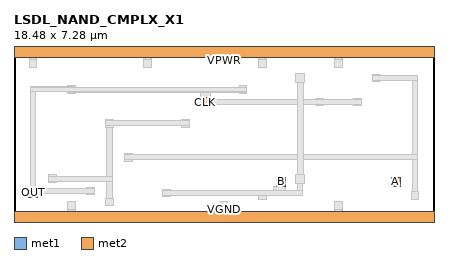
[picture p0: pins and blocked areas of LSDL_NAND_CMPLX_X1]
MACRO LSDL_NAND_CMPLX_X1
 CLASS CORE ;
 FOREIGN LSDL_NAND_CMPLX_X1 0 0 ;
 SIZE 18.48 BY 7.28 ;
 ORIGIN 0 0 ;
 SYMMETRY X Y R90 ;
 SITE unit ;
  PIN VPWR
   DIRECTION INOUT ;
   USE POWER ;
   SHAPE ABUTMENT ;
    PORT
     CLASS CORE ;
       LAYER met1 ;
        RECT 0.00000000 7.04000000 18.48000000 7.52000000 ;
       LAYER met2 ;
        RECT 0.00000000 7.04000000 18.48000000 7.52000000 ;
    END
  END VPWR

  PIN VGND
   DIRECTION INOUT ;
   USE POWER ;
   SHAPE ABUTMENT ;
    PORT
     CLASS CORE ;
       LAYER met1 ;
        RECT 0.00000000 -0.24000000 18.48000000 0.24000000 ;
       LAYER met2 ;
        RECT 0.00000000 -0.24000000 18.48000000 0.24000000 ;
    END
  END VGND

  PIN OUT
   DIRECTION INOUT ;
   USE SIGNAL ;
   SHAPE ABUTMENT ;
    PORT
     CLASS CORE ;
       LAYER met2 ;
        RECT 0.64000000 0.86000000 1.04000000 1.26000000 ;
    END
  END OUT

  PIN CLK
   DIRECTION INOUT ;
   USE SIGNAL ;
   SHAPE ABUTMENT ;
    PORT
     CLASS CORE ;
       LAYER met2 ;
        RECT 8.20000000 4.85700000 8.60000000 5.25700000 ;
    END
  END CLK

  PIN B
   DIRECTION INOUT ;
   USE SIGNAL ;
   SHAPE ABUTMENT ;
    PORT
     CLASS CORE ;
       LAYER met2 ;
        RECT 11.56000000 1.34700000 11.96000000 1.74700000 ;
    END
  END B

  PIN A
   DIRECTION INOUT ;
   USE SIGNAL ;
   SHAPE ABUTMENT ;
    PORT
     CLASS CORE ;
       LAYER met2 ;
        RECT 16.60000000 1.34700000 17.00000000 1.74700000 ;
    END
  END A

 OBS
    LAYER polycont ;
     RECT 11.65000000 1.43700000 11.87000000 1.65700000 ;
     RECT 8.29000000 4.94700000 8.51000000 5.16700000 ;
     RECT 13.33000000 4.94700000 13.55000000 5.16700000 ;
     RECT 15.01000000 4.94700000 15.23000000 5.16700000 ;
     RECT 3.25000000 1.03200000 3.47000000 1.25200000 ;
     RECT 9.97000000 5.48700000 10.19000000 5.70700000 ;
     RECT 4.93000000 2.51700000 5.15000000 2.73700000 ;
     RECT 6.61000000 0.95000000 6.83000000 1.17000000 ;
     RECT 16.69000000 1.43700000 16.91000000 1.65700000 ;
     RECT 1.57000000 1.57200000 1.79000000 1.79200000 ;

    LAYER pdiffc ;
     RECT 2.41000000 5.51000000 2.63000000 5.73000000 ;
     RECT 0.73000000 6.65000000 0.95000000 6.87000000 ;
     RECT 5.77000000 6.65000000 5.99000000 6.87000000 ;
     RECT 10.81000000 6.65000000 11.03000000 6.87000000 ;
     RECT 14.17000000 6.65000000 14.39000000 6.87000000 ;
     RECT 15.85000000 6.01000000 16.07000000 6.23000000 ;
     RECT 12.49000000 6.01000000 12.71000000 6.23000000 ;
     RECT 4.09000000 4.01000000 4.31000000 4.23000000 ;
     RECT 7.45000000 4.01000000 7.67000000 4.23000000 ;

    LAYER ndiffc ;
     RECT 0.73000000 0.95000000 0.95000000 1.17000000 ;
     RECT 17.53000000 0.85000000 17.75000000 1.07000000 ;
     RECT 2.41000000 0.41000000 2.63000000 0.63000000 ;
     RECT 9.13000000 0.41000000 9.35000000 0.63000000 ;
     RECT 14.17000000 0.41000000 14.39000000 0.63000000 ;
     RECT 10.81000000 0.85000000 11.03000000 1.07000000 ;
     RECT 4.09000000 0.55000000 4.31000000 0.77000000 ;

    LAYER met1 ;
     RECT 2.35000000 0.24000000 2.40500000 0.35000000 ;
     RECT 2.63500000 0.24000000 2.69000000 0.35000000 ;
     RECT 9.07000000 0.24000000 9.12500000 0.35000000 ;
     RECT 9.35500000 0.24000000 9.41000000 0.35000000 ;
     RECT 14.11000000 0.24000000 14.16500000 0.35000000 ;
     RECT 14.39500000 0.24000000 14.45000000 0.35000000 ;
     RECT 11.40700000 1.17500000 11.96000000 1.34700000 ;
     RECT 8.60000000 5.17200000 8.86200000 5.25700000 ;
     RECT 8.20000000 5.25700000 8.64800000 5.48200000 ;
     RECT 0.67000000 6.93000000 0.72500000 7.04000000 ;
     RECT 0.95500000 6.93000000 1.01000000 7.04000000 ;
     RECT 5.71000000 6.93000000 5.76500000 7.04000000 ;
     RECT 5.99500000 6.93000000 6.05000000 7.04000000 ;
     RECT 10.75000000 6.93000000 10.80500000 7.04000000 ;
     RECT 11.03500000 6.93000000 11.09000000 7.04000000 ;
     RECT 14.11000000 6.93000000 14.16500000 7.04000000 ;
     RECT 14.39500000 6.93000000 14.45000000 7.04000000 ;
     RECT 11.56000000 1.34700000 11.96000000 1.74700000 ;
     RECT 8.20000000 4.85700000 8.60000000 4.94200000 ;
     RECT 13.27000000 4.88700000 13.61000000 4.94200000 ;
     RECT 14.95000000 4.88700000 15.29000000 4.94200000 ;
     RECT 8.20000000 4.94200000 15.29000000 5.17200000 ;
     RECT 13.27000000 5.17200000 13.61000000 5.22700000 ;
     RECT 14.95000000 5.17200000 15.29000000 5.22700000 ;
     RECT 8.20000000 5.17200000 8.60000000 5.25700000 ;
     RECT 0.64000000 0.86000000 1.04000000 1.02700000 ;
     RECT 3.19000000 0.97200000 3.53000000 1.02700000 ;
     RECT 0.64000000 1.02700000 3.53000000 1.25700000 ;
     RECT 0.64000000 1.25700000 1.04000000 1.26000000 ;
     RECT 3.19000000 1.25700000 3.53000000 1.31200000 ;
     RECT 2.35000000 5.45000000 2.69000000 5.48200000 ;
     RECT 9.91000000 5.42700000 10.25000000 5.48200000 ;
     RECT 0.72500000 1.26000000 0.95500000 5.50500000 ;
     RECT 2.35000000 5.48200000 10.25000000 5.50500000 ;
     RECT 0.72500000 5.50500000 10.25000000 5.71200000 ;
     RECT 0.72500000 5.71200000 2.69000000 5.73500000 ;
     RECT 9.91000000 5.71200000 10.25000000 5.76700000 ;
     RECT 2.35000000 5.73500000 2.69000000 5.79000000 ;
     RECT 0.67000000 6.59000000 1.01000000 6.93000000 ;
     RECT 5.71000000 6.59000000 6.05000000 6.93000000 ;
     RECT 10.75000000 6.59000000 11.09000000 6.93000000 ;
     RECT 14.11000000 6.59000000 14.45000000 6.93000000 ;
     RECT 0.72500000 6.93000000 0.95500000 7.04000000 ;
     RECT 5.76500000 6.93000000 5.99500000 7.04000000 ;
     RECT 10.80500000 6.93000000 11.03500000 7.04000000 ;
     RECT 14.16500000 6.93000000 14.39500000 7.04000000 ;
     RECT 0.00000000 7.04000000 18.48000000 7.52000000 ;
     RECT 17.47000000 0.79000000 17.81000000 1.13000000 ;
     RECT 4.87000000 2.45700000 5.21000000 2.51200000 ;
     RECT 17.52500000 1.13000000 17.75500000 2.51200000 ;
     RECT 4.87000000 2.51200000 17.75500000 2.74200000 ;
     RECT 4.87000000 2.74200000 5.21000000 2.79700000 ;
     RECT 15.79000000 5.95000000 16.13000000 6.00500000 ;
     RECT 17.52500000 2.74200000 17.75500000 6.00500000 ;
     RECT 15.79000000 6.00500000 17.75500000 6.23500000 ;
     RECT 15.79000000 6.23500000 16.13000000 6.29000000 ;
     RECT 0.00000000 -0.24000000 18.48000000 0.24000000 ;
     RECT 2.40500000 0.24000000 2.63500000 0.35000000 ;
     RECT 9.12500000 0.24000000 9.35500000 0.35000000 ;
     RECT 14.16500000 0.24000000 14.39500000 0.35000000 ;
     RECT 2.35000000 0.35000000 2.69000000 0.69000000 ;
     RECT 9.07000000 0.35000000 9.41000000 0.69000000 ;
     RECT 14.11000000 0.35000000 14.45000000 0.69000000 ;
     RECT 6.55000000 0.89000000 6.89000000 0.94500000 ;
     RECT 10.75000000 0.79000000 11.09000000 0.94500000 ;
     RECT 6.55000000 0.94500000 12.71500000 1.17500000 ;
     RECT 6.55000000 1.17500000 6.89000000 1.23000000 ;
     RECT 12.48500000 1.17500000 12.71500000 1.48200000 ;
     RECT 12.40000000 1.48200000 12.80000000 1.88200000 ;
     RECT 12.40000000 5.92000000 12.80000000 6.32000000 ;
     RECT 16.60000000 1.34700000 17.00000000 1.74700000 ;
     RECT 4.03000000 0.49000000 4.37000000 0.83000000 ;
     RECT 1.51000000 1.51200000 1.85000000 1.56700000 ;
     RECT 4.08500000 0.83000000 4.31500000 1.56700000 ;
     RECT 1.51000000 1.56700000 4.31500000 1.79700000 ;
     RECT 1.51000000 1.79700000 1.85000000 1.85200000 ;
     RECT 4.08500000 1.79700000 4.31500000 3.95000000 ;
     RECT 4.03000000 3.95000000 4.37000000 4.00500000 ;
     RECT 7.39000000 3.95000000 7.73000000 4.00500000 ;
     RECT 4.03000000 4.00500000 7.73000000 4.23500000 ;
     RECT 4.03000000 4.23500000 4.37000000 4.29000000 ;
     RECT 7.39000000 4.23500000 7.73000000 4.29000000 ;

    LAYER via1 ;
     RECT 11.63000000 1.41700000 11.89000000 1.67700000 ;
     RECT 8.27000000 4.92700000 8.53000000 5.18700000 ;
     RECT 0.71000000 0.93000000 0.97000000 1.19000000 ;
     RECT 0.71000000 7.15000000 0.97000000 7.41000000 ;
     RECT 2.39000000 7.15000000 2.65000000 7.41000000 ;
     RECT 4.07000000 7.15000000 4.33000000 7.41000000 ;
     RECT 5.75000000 7.15000000 6.01000000 7.41000000 ;
     RECT 7.43000000 7.15000000 7.69000000 7.41000000 ;
     RECT 9.11000000 7.15000000 9.37000000 7.41000000 ;
     RECT 10.79000000 7.15000000 11.05000000 7.41000000 ;
     RECT 12.47000000 7.15000000 12.73000000 7.41000000 ;
     RECT 14.15000000 7.15000000 14.41000000 7.41000000 ;
     RECT 15.83000000 7.15000000 16.09000000 7.41000000 ;
     RECT 17.51000000 7.15000000 17.77000000 7.41000000 ;
     RECT 0.71000000 -0.13000000 0.97000000 0.13000000 ;
     RECT 2.39000000 -0.13000000 2.65000000 0.13000000 ;
     RECT 4.07000000 -0.13000000 4.33000000 0.13000000 ;
     RECT 5.75000000 -0.13000000 6.01000000 0.13000000 ;
     RECT 7.43000000 -0.13000000 7.69000000 0.13000000 ;
     RECT 9.11000000 -0.13000000 9.37000000 0.13000000 ;
     RECT 10.79000000 -0.13000000 11.05000000 0.13000000 ;
     RECT 12.47000000 -0.13000000 12.73000000 0.13000000 ;
     RECT 14.15000000 -0.13000000 14.41000000 0.13000000 ;
     RECT 15.83000000 -0.13000000 16.09000000 0.13000000 ;
     RECT 17.51000000 -0.13000000 17.77000000 0.13000000 ;
     RECT 12.47000000 1.55200000 12.73000000 1.81200000 ;
     RECT 12.47000000 5.99000000 12.73000000 6.25000000 ;
     RECT 16.67000000 1.41700000 16.93000000 1.67700000 ;

    LAYER met2 ;
     RECT 11.56000000 1.34700000 11.96000000 1.74700000 ;
     RECT 8.20000000 4.85700000 8.60000000 5.25700000 ;
     RECT 0.64000000 0.86000000 1.04000000 1.26000000 ;
     RECT 0.00000000 7.04000000 18.48000000 7.52000000 ;
     RECT 0.00000000 -0.24000000 18.48000000 0.24000000 ;
     RECT 12.40000000 1.48200000 12.80000000 1.88200000 ;
     RECT 12.46000000 1.88200000 12.74000000 5.92000000 ;
     RECT 12.40000000 5.92000000 12.80000000 6.32000000 ;
     RECT 16.60000000 1.34700000 17.00000000 1.74700000 ;

 END
END LSDL_NAND_CMPLX_X1
